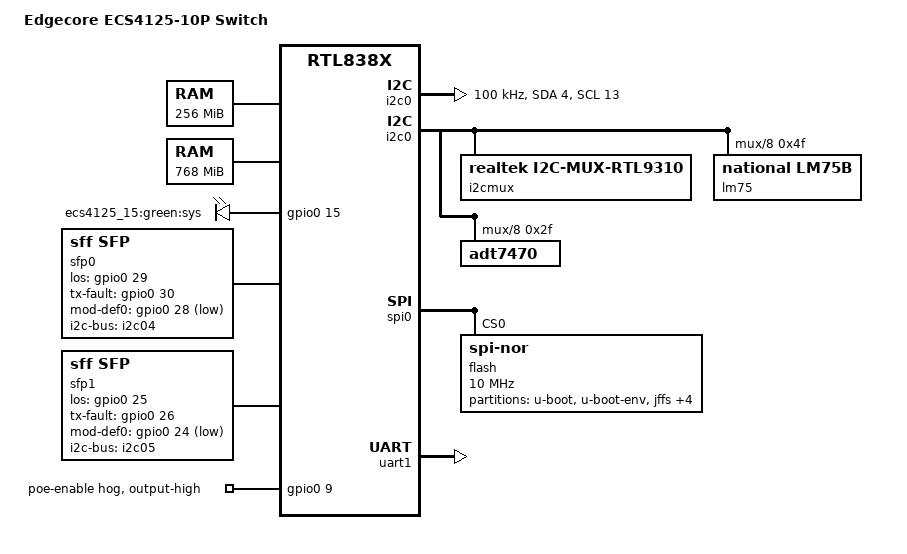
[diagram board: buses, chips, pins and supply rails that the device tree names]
/dts-v1/;

#include "rtl931x.dtsi"

#include <dt-bindings/input/input.h>
#include <dt-bindings/gpio/gpio.h>

/ {
	compatible = "edgecore,ecs4125-10p", "realtek,rtl838x-soc";
	model = "Edgecore ECS4125-10P Switch";

	aliases {
		led-boot = &led_sys;
		led-failsafe = &led_sys;
		led-running = &led_sys;
		led-upgrade = &led_sys;
	};	

	memory@0 {
		device_type = "memory";
		reg = <0x0 0x10000000>;
	};

	memory@90000000 {
		device_type = "memory";
		reg = <0x90000000 0x30000000>;
	};

	chosen {
		bootargs = "console=ttyS0,115200";
	};

	leds {
		compatible = "gpio-leds";

		led_sys: sys {
			label = "ecs4125_15:green:sys";
			gpios = <&gpio0 15 GPIO_ACTIVE_HIGH>;
		};
	};

	i2c0: i2c-rtl9310 {
		compatible = "realtek,rtl931x-i2c";
		reg = <0x1b001004 0x3c>;
		#address-cells = <1>;
		#size-cells = <0>;
		sda-pin = <4>;
		scl-pin = <13>;
		clock-frequency = <100000>;
	};

	i2cmux {
		compatible = "realtek,i2c-mux-rtl9310";
		#address-cells = <1>;
		#size-cells = <0>;
		i2c-parent = <&i2c0>;

		i2c04: i2c-rtl9310-0-4 {
			reg = <4>;
			#address-cells = <1>;
			#size-cells = <0>;
			sda-pin = <4>;
			scl-pin = <13>;
		};

		i2c05: i2c-rtl9310-0-5 {
			reg = <5>;
			#address-cells = <1>;
			#size-cells = <0>;
			sda-pin = <5>;
			scl-pin = <13>;
		};

		i2c10: i2c-rtl9310-1-0 {
			reg = <8>;
			#address-cells = <1>;
			#size-cells = <0>;
			sda-pin = <0>;
			scl-pin = <14>;

			lm75: sensorlm75@4f {
				compatible = "national,lm75b";
				reg = <0x4f>;
			};

			adt7470@2f {
				compatible = "adt7470";
				reg = <0x2f>;
			};

		};
	};

	sfp0: sfp-p0 {
		compatible = "sff,sfp";
		i2c-bus = <&i2c04>;
		los-gpio = <&gpio0 29 GPIO_ACTIVE_HIGH>;
		tx-fault-gpio = <&gpio0 30 GPIO_ACTIVE_HIGH>;
		mod-def0-gpio = <&gpio0 28 GPIO_ACTIVE_LOW>;
//		tx-disable-gpio = <&gpio0 31 GPIO_ACTIVE_HIGH>;
	};

	sfp1: sfp-p1 {
		compatible = "sff,sfp";
		i2c-bus = <&i2c05>;
		los-gpio = <&gpio0 25 GPIO_ACTIVE_HIGH>;
		tx-fault-gpio = <&gpio0 26 GPIO_ACTIVE_HIGH>;
		mod-def0-gpio = <&gpio0 24 GPIO_ACTIVE_LOW>;
//		tx-disable-gpio = <&gpio0 27 GPIO_ACTIVE_HIGH>;
	};
/*
&gpio0 {
	indirect-access-bus-id = <0>;
	};
*/
};

&gpio0 {
	poe_enable_hog {
		gpio-hog;
		gpios = <9 GPIO_ACTIVE_HIGH>;
		output-high;
		line-name = "poe-enable";
	};
};

#if 0
&i2c_mst1 {
	status = "okay";

	/* i2c of the left SFP+ cage seen from the front; port 11 */
	i2c4: i2c@4 { 
	reg = <4>; 
	};

	/* i2c of the right SFP+ cage seen from the front; port 12 */
	i2c5: i2c@5 {  
	reg = <5>; 
	};

};
&i2c_mst2 {
	status = "okay";

	i2c12: i2c@12 {
		reg = <0>;
		lm75: sensorlm75@4f {
			compatible = "national,lm75b";
			reg = <0x4f>;
		};

		adt7470@2f {
			compatible = "adt7470";
			reg = <0x2f>;
		};

		eeprom@57 {
			compatible = "atmel,24c32";
			reg = <0x57>;
		};
	};

};
#endif

&spi0 {
	status = "okay";
	flash@0 {
		compatible = "jedec,spi-nor";
		reg = <0>;
		spi-max-frequency = <10000000>;

		partitions {
			compatible = "fixed-partitions";
			#address-cells = <1>;
			#size-cells = <1>;

			partition@0 {
				label = "u-boot";
				reg = <0x0 0x100000>;
			};
			partition@100000 {
				label = "u-boot-env";
				reg = <0x100000 0x10000>;
			};
			partition@120000 {
				label = "jffs";
				reg = <0x120000 0x100000>;
			};
			partition@220000 {
				label = "jffs2";
				reg = <0x220000 0x100000>;
			};
			partition@320000 {
				label = "linux";
				reg = <0x320000 0x1e60000>;
				compatible = "openwrt,uimage", "denx,uimage";
			};
			partition@2180000 {
				label = "nvram";
				reg = <0x2180000 0x20000>;
			};
			partition@2200000 {
				label = "runtime2";
				reg = <0x2200000 0x1e00000>;
			};
		};
	};
};

&mdio_ctrl {
	pinctrl-names = "default";
	pinctrl-0 = <&pinmux_enable_mdc_mdio_0>,
		    <&pinmux_enable_mdc_mdio_1>;
};

&mdio_bus0 {
	PHY_C45(0, 4)
	PHY_C45(8, 2)
	PHY_C45(16, 6)
	PHY_C45(24, 1)
};
&mdio_bus1 {
	PHY_C45(32, 4)
	PHY_C45(40, 2)
	PHY_C45(48, 6)
	PHY_C45(50, 1)
};

&switch0 {
	ethernet-ports {
		#address-cells = <1>;
		#size-cells = <0>;

		port@0 {
			reg = <0>;
			label = "lan2";
			pcs-handle = <&serdes2 0>;
			phy-handle = <&phy0>;
			phy-mode = "hsgmii";
			managed = "in-band-status";
			led-set = <0>;
		};

		port@8 {
			reg = <8>;
			label = "lan1";
			pcs-handle = <&serdes3 0>;
			phy-handle = <&phy8>;
			phy-mode = "hsgmii";
			managed = "in-band-status";
			led-set = <0>;
		};

		port@16 {
			reg = <16>;
			label = "lan3";
			pcs-handle = <&serdes4 0>;
			phy-handle = <&phy16>;
			phy-mode = "hsgmii";
			managed = "in-band-status";
			led-set = <0>;
		};

		port@24 {
			reg = <24>;
			label = "lan4";
			pcs-handle = <&serdes5 0>;
			phy-handle = <&phy24>;
			phy-mode = "hsgmii";
			managed = "in-band-status";
			led-set = <0>;
		};

		port@32 {
			reg = <32>;
			label = "lan5";
			pcs-handle = <&serdes6 0>;
			phy-handle = <&phy32>;
			phy-mode = "hsgmii";
			managed = "in-band-status";
			led-set = <0>;
		};

		port@40 {
			reg = <40>;
			label = "lan6";
			pcs-handle = <&serdes7 0>;
			phy-handle = <&phy40>;
			phy-mode = "hsgmii";
			managed = "in-band-status";
			led-set = <0>;
		};

		port@48 {
			reg = <48>;
			label = "lan7";
			pcs-handle = <&serdes8 0>;
			phy-handle = <&phy48>;
			phy-mode = "hsgmii";
			managed = "in-band-status";
			led-set = <0>;
		};

		port@50 {
			reg = <50>;
			label = "lan8";
			pcs-handle = <&serdes9 0>;
			phy-handle = <&phy50>;
			phy-mode = "hsgmii";
			managed = "in-band-status";
			led-set = <0>;
		};

		SWITCH_PORT_SFP(54, 9, 12, 0, 0)
		SWITCH_PORT_SFP(55, 10, 13, 0, 1)

		/* CPU port */
		port@56 {
			ethernet = <&ethernet0>;
			reg = <56>;
			phy-mode = "internal";
			fixed-link {
				speed = <1000>;
				full-duplex;
			};
		};
	};
};

&uart1 {
	status = "okay";
};
